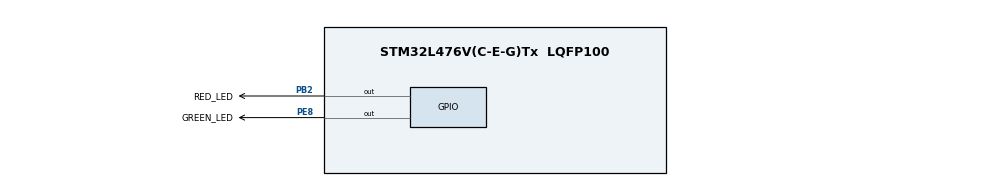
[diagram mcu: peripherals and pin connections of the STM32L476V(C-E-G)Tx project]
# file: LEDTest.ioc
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Mcu.Family=STM32L4
Mcu.Name=STM32L476V(C-E-G)Tx
Mcu.Package=LQFP100
NVIC.PriorityGroup=NVIC_PRIORITYGROUP_4
PA13.Mode=Serial-Wire
PA13.Signal=SYS_JTMS-SWDIO
PA14.GPIO_Label=SWCLK
PA14.Mode=Serial-Wire
PA14.Signal=SYS_JTCK-SWCLK
PB2.GPIO_Label=RED_LED
PB2.GPIO_ModeDefaultOutputPP=GPIO_MODE_OUTPUT_PP
PB2.GPIO_PuPd=GPIO_PULLUP
PB2.GPIO_Speed=GPIO_SPEED_HIGH
PB2.Signal=GPIO_Output
PE8.GPIO_Label=GREEN_LED
PE8.GPIO_PuPd=GPIO_PULLUP
PE8.GPIO_Speed=GPIO_SPEED_HIGH
PE8.Signal=GPIO_Output
ProjectManager.TargetToolchain=SW4STM32
RCC.ADCFreq_Value=64000000
RCC.AHBFreq_Value=64000000
RCC.APB1Freq_Value=64000000
RCC.APB1TimFreq_Value=64000000
RCC.APB2Freq_Value=64000000
RCC.APB2TimFreq_Value=64000000
RCC.CortexFreq_Value=64000000
RCC.HCLKFreq_Value=64000000
RCC.HSE_VALUE=8000000
RCC.HSI_VALUE=16000000
RCC.MSI_VALUE=4000000
RCC.PLLSourceVirtual=RCC_PLLSOURCE_HSI
RCC.PREFETCH_ENABLE=1
RCC.SYSCLKFreq_VALUE=64000000
RCC.SYSCLKSource=RCC_SYSCLKSOURCE_PLLCLK
RCC.USBFreq_Value=64000000
RCC.VCOOutputFreq_Value=128000000
board=STM32L476G-DISCO

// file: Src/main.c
/**
  ******************************************************************************
  * File Name          : main.c
  * Description        : Main program body
  ******************************************************************************
  *
  * COPYRIGHT(c) 2015 STMicroelectronics
  *
  * Redistribution and use in source and binary forms, with or without modification,
  * are permitted provided that the following conditions are met:
  *   1. Redistributions of source code must retain the above copyright notice,
  *      this list of conditions and the following disclaimer.
  *   2. Redistributions in binary form must reproduce the above copyright notice,
  *      this list of conditions and the following disclaimer in the documentation
  *      and/or other materials provided with the distribution.
  *   3. Neither the name of STMicroelectronics nor the names of its contributors
  *      may be used to endorse or promote products derived from this software
  *      without specific prior written permission.
  *
  * THIS SOFTWARE IS PROVIDED BY THE COPYRIGHT HOLDERS AND CONTRIBUTORS "AS IS"
  * AND ANY EXPRESS OR IMPLIED WARRANTIES, INCLUDING, BUT NOT LIMITED TO, THE
  * IMPLIED WARRANTIES OF MERCHANTABILITY AND FITNESS FOR A PARTICULAR PURPOSE ARE
  * DISCLAIMED. IN NO EVENT SHALL THE COPYRIGHT HOLDER OR CONTRIBUTORS BE LIABLE
  * FOR ANY DIRECT, INDIRECT, INCIDENTAL, SPECIAL, EXEMPLARY, OR CONSEQUENTIAL
  * DAMAGES (INCLUDING, BUT NOT LIMITED TO, PROCUREMENT OF SUBSTITUTE GOODS OR
  * SERVICES; LOSS OF USE, DATA, OR PROFITS; OR BUSINESS INTERRUPTION) HOWEVER
  * CAUSED AND ON ANY THEORY OF LIABILITY, WHETHER IN CONTRACT, STRICT LIABILITY,
  * OR TORT (INCLUDING NEGLIGENCE OR OTHERWISE) ARISING IN ANY WAY OUT OF THE USE
  * OF THIS SOFTWARE, EVEN IF ADVISED OF THE POSSIBILITY OF SUCH DAMAGE.
  *
  ******************************************************************************
  */
#include "stm32l4xx_hal.h"

/* USER CODE BEGIN PV */
/* Private variables ---------------------------------------------------------*/

/* USER CODE END PV */

void SystemClock_Config(void);
static void MX_GPIO_Init(void);

/* USER CODE BEGIN PFP */
/* Private function prototypes -----------------------------------------------*/

/* USER CODE END PFP */

int main(void)
{

  /* MCU Configuration----------------------------------------------------------*/

  /* Reset of all peripherals, Initializes the Flash interface and the Systick. */
  HAL_Init();

  /* Configure the system clock */
  SystemClock_Config();

  /* Initialize all configured peripherals */
  MX_GPIO_Init();

  /* Infinite loop */
  while (1)
  {
HAL_GPIO_WritePin(RED_LED_GPIO_Port, RED_LED_Pin, GPIO_PIN_SET);
    HAL_GPIO_WritePin(GREEN_LED_GPIO_Port, GREEN_LED_Pin, GPIO_PIN_SET);

    HAL_Delay(500);

    HAL_GPIO_WritePin(RED_LED_GPIO_Port, RED_LED_Pin, GPIO_PIN_RESET);
    HAL_GPIO_WritePin(GREEN_LED_GPIO_Port, GREEN_LED_Pin, GPIO_PIN_RESET);

    HAL_Delay(500);
  }

}

/** System Clock Configuration
*/
void SystemClock_Config(void)
{

  RCC_OscInitTypeDef RCC_OscInitStruct;
  RCC_ClkInitTypeDef RCC_ClkInitStruct;

  RCC_OscInitStruct.OscillatorType = RCC_OSCILLATORTYPE_MSI;
  RCC_OscInitStruct.MSIState = RCC_MSI_ON;
  RCC_OscInitStruct.MSICalibrationValue = 0;
  RCC_OscInitStruct.MSIClockRange = RCC_MSIRANGE_6;
  RCC_OscInitStruct.PLL.PLLState = RCC_PLL_NONE;
  HAL_RCC_OscConfig(&RCC_OscInitStruct);

  RCC_ClkInitStruct.ClockType = RCC_CLOCKTYPE_HCLK|RCC_CLOCKTYPE_SYSCLK
                              |RCC_CLOCKTYPE_PCLK1|RCC_CLOCKTYPE_PCLK2;
  RCC_ClkInitStruct.SYSCLKSource = RCC_SYSCLKSOURCE_MSI;
  RCC_ClkInitStruct.AHBCLKDivider = RCC_SYSCLK_DIV1;
  RCC_ClkInitStruct.APB1CLKDivider = RCC_HCLK_DIV1;
  RCC_ClkInitStruct.APB2CLKDivider = RCC_HCLK_DIV1;
  HAL_RCC_ClockConfig(&RCC_ClkInitStruct, FLASH_LATENCY_0);

  __PWR_CLK_ENABLE();

  HAL_PWREx_ControlVoltageScaling(PWR_REGULATOR_VOLTAGE_SCALE1);

  HAL_SYSTICK_Config(HAL_RCC_GetHCLKFreq()/1000);

  HAL_SYSTICK_CLKSourceConfig(SYSTICK_CLKSOURCE_HCLK);

  /* SysTick_IRQn interrupt configuration */
  HAL_NVIC_SetPriority(SysTick_IRQn, 0, 0);
}

/** Configure pins as
        * Analog
        * Input
        * Output
        * EVENT_OUT
        * EXTI
*/
void MX_GPIO_Init(void)
{

  GPIO_InitTypeDef GPIO_InitStruct;

  /* GPIO Ports Clock Enable */
  __GPIOB_CLK_ENABLE();
  __GPIOE_CLK_ENABLE();
  __GPIOA_CLK_ENABLE();

  /*Configure GPIO pin : RED_LED_Pin */
  GPIO_InitStruct.Pin = RED_LED_Pin;
  GPIO_InitStruct.Mode = GPIO_MODE_OUTPUT_PP;
  GPIO_InitStruct.Pull = GPIO_PULLUP;
  GPIO_InitStruct.Speed = GPIO_SPEED_HIGH;
  HAL_GPIO_Init(RED_LED_GPIO_Port, &GPIO_InitStruct);

  /*Configure GPIO pin : GREEN_LED_Pin */
  GPIO_InitStruct.Pin = GREEN_LED_Pin;
  GPIO_InitStruct.Mode = GPIO_MODE_OUTPUT_PP;
  GPIO_InitStruct.Pull = GPIO_PULLUP;
  GPIO_InitStruct.Speed = GPIO_SPEED_HIGH;
  HAL_GPIO_Init(GREEN_LED_GPIO_Port, &GPIO_InitStruct);

}

/************************ (C) COPYRIGHT STMicroelectronics *****END OF FILE****/
